###############################################################
#  Generated by:      Cadence Innovus 22.17-s086_1
#  OS:                Linux x86_64(Host ID vlsiktmt)
#  Generated on:      Sun Apr 12 21:09:17 2026
#  Design:            Adder32
#  Command:           write_lef_abstract -noCutObs ./outputs/innovus.lef
###############################################################

VERSION 5.8 ;

BUSBITCHARS "[]" ;
DIVIDERCHAR "/" ;

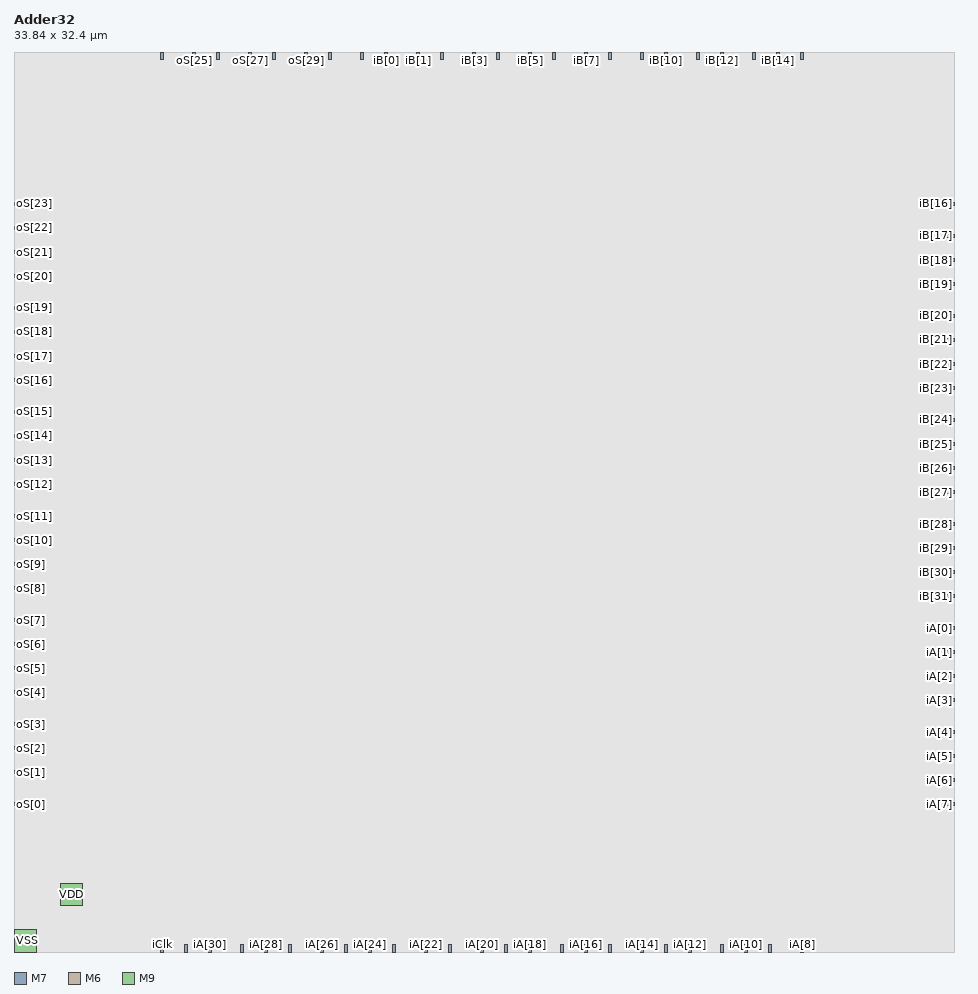
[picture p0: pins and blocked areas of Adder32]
MACRO Adder32
  CLASS BLOCK ;
  SIZE 33.840000 BY 32.400000 ;
  FOREIGN Adder32 0.000000 0.000000 ;
  ORIGIN 0 0 ;
  SYMMETRY X Y R90 ;
  PIN iClk
    DIRECTION INPUT ;
    USE SIGNAL ;
    PORT
      LAYER M7 ;
        RECT 5.264000 0.000000 5.392000 0.280000 ;
    END
  END iClk
  PIN iA[31]
    DIRECTION INPUT ;
    USE SIGNAL ;
    PORT
      LAYER M7 ;
        RECT 6.128000 0.000000 6.256000 0.280000 ;
    END
  END iA[31]
  PIN iA[30]
    DIRECTION INPUT ;
    USE SIGNAL ;
    PORT
      LAYER M7 ;
        RECT 6.992000 0.000000 7.120000 0.280000 ;
    END
  END iA[30]
  PIN iA[29]
    DIRECTION INPUT ;
    USE SIGNAL ;
    PORT
      LAYER M7 ;
        RECT 8.144000 0.000000 8.272000 0.280000 ;
    END
  END iA[29]
  PIN iA[28]
    DIRECTION INPUT ;
    USE SIGNAL ;
    PORT
      LAYER M7 ;
        RECT 9.008000 0.000000 9.136000 0.280000 ;
    END
  END iA[28]
  PIN iA[27]
    DIRECTION INPUT ;
    USE SIGNAL ;
    PORT
      LAYER M7 ;
        RECT 9.872000 0.000000 10.000000 0.280000 ;
    END
  END iA[27]
  PIN iA[26]
    DIRECTION INPUT ;
    USE SIGNAL ;
    PORT
      LAYER M7 ;
        RECT 11.024000 0.000000 11.152000 0.280000 ;
    END
  END iA[26]
  PIN iA[25]
    DIRECTION INPUT ;
    USE SIGNAL ;
    PORT
      LAYER M7 ;
        RECT 11.888000 0.000000 12.016000 0.280000 ;
    END
  END iA[25]
  PIN iA[24]
    DIRECTION INPUT ;
    USE SIGNAL ;
    PORT
      LAYER M7 ;
        RECT 12.752000 0.000000 12.880000 0.280000 ;
    END
  END iA[24]
  PIN iA[23]
    DIRECTION INPUT ;
    USE SIGNAL ;
    PORT
      LAYER M7 ;
        RECT 13.616000 0.000000 13.744000 0.280000 ;
    END
  END iA[23]
  PIN iA[22]
    DIRECTION INPUT ;
    USE SIGNAL ;
    PORT
      LAYER M7 ;
        RECT 14.768000 0.000000 14.896000 0.280000 ;
    END
  END iA[22]
  PIN iA[21]
    DIRECTION INPUT ;
    USE SIGNAL ;
    PORT
      LAYER M7 ;
        RECT 15.632000 0.000000 15.760000 0.280000 ;
    END
  END iA[21]
  PIN iA[20]
    DIRECTION INPUT ;
    USE SIGNAL ;
    PORT
      LAYER M7 ;
        RECT 16.784000 0.000000 16.912000 0.280000 ;
    END
  END iA[20]
  PIN iA[19]
    DIRECTION INPUT ;
    USE SIGNAL ;
    PORT
      LAYER M7 ;
        RECT 17.648000 0.000000 17.776000 0.280000 ;
    END
  END iA[19]
  PIN iA[18]
    DIRECTION INPUT ;
    USE SIGNAL ;
    PORT
      LAYER M7 ;
        RECT 18.512000 0.000000 18.640000 0.280000 ;
    END
  END iA[18]
  PIN iA[17]
    DIRECTION INPUT ;
    USE SIGNAL ;
    PORT
      LAYER M7 ;
        RECT 19.664000 0.000000 19.792000 0.280000 ;
    END
  END iA[17]
  PIN iA[16]
    DIRECTION INPUT ;
    USE SIGNAL ;
    PORT
      LAYER M7 ;
        RECT 20.528000 0.000000 20.656000 0.280000 ;
    END
  END iA[16]
  PIN iA[15]
    DIRECTION INPUT ;
    USE SIGNAL ;
    PORT
      LAYER M7 ;
        RECT 21.392000 0.000000 21.520000 0.280000 ;
    END
  END iA[15]
  PIN iA[14]
    DIRECTION INPUT ;
    USE SIGNAL ;
    PORT
      LAYER M7 ;
        RECT 22.544000 0.000000 22.672000 0.280000 ;
    END
  END iA[14]
  PIN iA[13]
    DIRECTION INPUT ;
    USE SIGNAL ;
    PORT
      LAYER M7 ;
        RECT 23.408000 0.000000 23.536000 0.280000 ;
    END
  END iA[13]
  PIN iA[12]
    DIRECTION INPUT ;
    USE SIGNAL ;
    PORT
      LAYER M7 ;
        RECT 24.272000 0.000000 24.400000 0.280000 ;
    END
  END iA[12]
  PIN iA[11]
    DIRECTION INPUT ;
    USE SIGNAL ;
    PORT
      LAYER M7 ;
        RECT 25.424000 0.000000 25.552000 0.280000 ;
    END
  END iA[11]
  PIN iA[10]
    DIRECTION INPUT ;
    USE SIGNAL ;
    PORT
      LAYER M7 ;
        RECT 26.288000 0.000000 26.416000 0.280000 ;
    END
  END iA[10]
  PIN iA[9]
    DIRECTION INPUT ;
    USE SIGNAL ;
    PORT
      LAYER M7 ;
        RECT 27.152000 0.000000 27.280000 0.280000 ;
    END
  END iA[9]
  PIN iA[8]
    DIRECTION INPUT ;
    USE SIGNAL ;
    PORT
      LAYER M7 ;
        RECT 28.304000 0.000000 28.432000 0.280000 ;
    END
  END iA[8]
  PIN iA[7]
    DIRECTION INPUT ;
    USE SIGNAL ;
    PORT
      LAYER M6 ;
        RECT 33.560000 5.264000 33.840000 5.392000 ;
    END
  END iA[7]
  PIN iA[6]
    DIRECTION INPUT ;
    USE SIGNAL ;
    PORT
      LAYER M6 ;
        RECT 33.560000 6.128000 33.840000 6.256000 ;
    END
  END iA[6]
  PIN iA[5]
    DIRECTION INPUT ;
    USE SIGNAL ;
    PORT
      LAYER M6 ;
        RECT 33.560000 6.992000 33.840000 7.120000 ;
    END
  END iA[5]
  PIN iA[4]
    DIRECTION INPUT ;
    USE SIGNAL ;
    PORT
      LAYER M6 ;
        RECT 33.560000 7.856000 33.840000 7.984000 ;
    END
  END iA[4]
  PIN iA[3]
    DIRECTION INPUT ;
    USE SIGNAL ;
    PORT
      LAYER M6 ;
        RECT 33.560000 9.008000 33.840000 9.136000 ;
    END
  END iA[3]
  PIN iA[2]
    DIRECTION INPUT ;
    USE SIGNAL ;
    PORT
      LAYER M6 ;
        RECT 33.560000 9.872000 33.840000 10.000000 ;
    END
  END iA[2]
  PIN iA[1]
    DIRECTION INPUT ;
    USE SIGNAL ;
    PORT
      LAYER M6 ;
        RECT 33.560000 10.736000 33.840000 10.864000 ;
    END
  END iA[1]
  PIN iA[0]
    DIRECTION INPUT ;
    USE SIGNAL ;
    PORT
      LAYER M6 ;
        RECT 33.560000 11.600000 33.840000 11.728000 ;
    END
  END iA[0]
  PIN iB[31]
    DIRECTION INPUT ;
    USE SIGNAL ;
    PORT
      LAYER M6 ;
        RECT 33.560000 12.752000 33.840000 12.880000 ;
    END
  END iB[31]
  PIN iB[30]
    DIRECTION INPUT ;
    USE SIGNAL ;
    PORT
      LAYER M6 ;
        RECT 33.560000 13.616000 33.840000 13.744000 ;
    END
  END iB[30]
  PIN iB[29]
    DIRECTION INPUT ;
    USE SIGNAL ;
    PORT
      LAYER M6 ;
        RECT 33.560000 14.480000 33.840000 14.608000 ;
    END
  END iB[29]
  PIN iB[28]
    DIRECTION INPUT ;
    USE SIGNAL ;
    PORT
      LAYER M6 ;
        RECT 33.560000 15.344000 33.840000 15.472000 ;
    END
  END iB[28]
  PIN iB[27]
    DIRECTION INPUT ;
    USE SIGNAL ;
    PORT
      LAYER M6 ;
        RECT 33.560000 16.496000 33.840000 16.624000 ;
    END
  END iB[27]
  PIN iB[26]
    DIRECTION INPUT ;
    USE SIGNAL ;
    PORT
      LAYER M6 ;
        RECT 33.560000 17.360000 33.840000 17.488000 ;
    END
  END iB[26]
  PIN iB[25]
    DIRECTION INPUT ;
    USE SIGNAL ;
    PORT
      LAYER M6 ;
        RECT 33.560000 18.224000 33.840000 18.352000 ;
    END
  END iB[25]
  PIN iB[24]
    DIRECTION INPUT ;
    USE SIGNAL ;
    PORT
      LAYER M6 ;
        RECT 33.560000 19.088000 33.840000 19.216000 ;
    END
  END iB[24]
  PIN iB[23]
    DIRECTION INPUT ;
    USE SIGNAL ;
    PORT
      LAYER M6 ;
        RECT 33.560000 20.240000 33.840000 20.368000 ;
    END
  END iB[23]
  PIN iB[22]
    DIRECTION INPUT ;
    USE SIGNAL ;
    PORT
      LAYER M6 ;
        RECT 33.560000 21.104000 33.840000 21.232000 ;
    END
  END iB[22]
  PIN iB[21]
    DIRECTION INPUT ;
    USE SIGNAL ;
    PORT
      LAYER M6 ;
        RECT 33.560000 21.968000 33.840000 22.096000 ;
    END
  END iB[21]
  PIN iB[20]
    DIRECTION INPUT ;
    USE SIGNAL ;
    PORT
      LAYER M6 ;
        RECT 33.560000 22.832000 33.840000 22.960000 ;
    END
  END iB[20]
  PIN iB[19]
    DIRECTION INPUT ;
    USE SIGNAL ;
    PORT
      LAYER M6 ;
        RECT 33.560000 23.984000 33.840000 24.112000 ;
    END
  END iB[19]
  PIN iB[18]
    DIRECTION INPUT ;
    USE SIGNAL ;
    PORT
      LAYER M6 ;
        RECT 33.560000 24.848000 33.840000 24.976000 ;
    END
  END iB[18]
  PIN iB[17]
    DIRECTION INPUT ;
    USE SIGNAL ;
    PORT
      LAYER M6 ;
        RECT 33.560000 25.712000 33.840000 25.840000 ;
    END
  END iB[17]
  PIN iB[16]
    DIRECTION INPUT ;
    USE SIGNAL ;
    PORT
      LAYER M6 ;
        RECT 33.560000 26.864000 33.840000 26.992000 ;
    END
  END iB[16]
  PIN iB[15]
    DIRECTION INPUT ;
    USE SIGNAL ;
    PORT
      LAYER M7 ;
        RECT 28.304000 32.120000 28.432000 32.400000 ;
    END
  END iB[15]
  PIN iB[14]
    DIRECTION INPUT ;
    USE SIGNAL ;
    PORT
      LAYER M7 ;
        RECT 27.440000 32.120000 27.568000 32.400000 ;
    END
  END iB[14]
  PIN iB[13]
    DIRECTION INPUT ;
    USE SIGNAL ;
    PORT
      LAYER M7 ;
        RECT 26.576000 32.120000 26.704000 32.400000 ;
    END
  END iB[13]
  PIN iB[12]
    DIRECTION INPUT ;
    USE SIGNAL ;
    PORT
      LAYER M7 ;
        RECT 25.424000 32.120000 25.552000 32.400000 ;
    END
  END iB[12]
  PIN iB[11]
    DIRECTION INPUT ;
    USE SIGNAL ;
    PORT
      LAYER M7 ;
        RECT 24.560000 32.120000 24.688000 32.400000 ;
    END
  END iB[11]
  PIN iB[10]
    DIRECTION INPUT ;
    USE SIGNAL ;
    PORT
      LAYER M7 ;
        RECT 23.408000 32.120000 23.536000 32.400000 ;
    END
  END iB[10]
  PIN iB[9]
    DIRECTION INPUT ;
    USE SIGNAL ;
    PORT
      LAYER M7 ;
        RECT 22.544000 32.120000 22.672000 32.400000 ;
    END
  END iB[9]
  PIN iB[8]
    DIRECTION INPUT ;
    USE SIGNAL ;
    PORT
      LAYER M7 ;
        RECT 21.392000 32.120000 21.520000 32.400000 ;
    END
  END iB[8]
  PIN iB[7]
    DIRECTION INPUT ;
    USE SIGNAL ;
    PORT
      LAYER M7 ;
        RECT 20.528000 32.120000 20.656000 32.400000 ;
    END
  END iB[7]
  PIN iB[6]
    DIRECTION INPUT ;
    USE SIGNAL ;
    PORT
      LAYER M7 ;
        RECT 19.376000 32.120000 19.504000 32.400000 ;
    END
  END iB[6]
  PIN iB[5]
    DIRECTION INPUT ;
    USE SIGNAL ;
    PORT
      LAYER M7 ;
        RECT 18.512000 32.120000 18.640000 32.400000 ;
    END
  END iB[5]
  PIN iB[4]
    DIRECTION INPUT ;
    USE SIGNAL ;
    PORT
      LAYER M7 ;
        RECT 17.360000 32.120000 17.488000 32.400000 ;
    END
  END iB[4]
  PIN iB[3]
    DIRECTION INPUT ;
    USE SIGNAL ;
    PORT
      LAYER M7 ;
        RECT 16.496000 32.120000 16.624000 32.400000 ;
    END
  END iB[3]
  PIN iB[2]
    DIRECTION INPUT ;
    USE SIGNAL ;
    PORT
      LAYER M7 ;
        RECT 15.344000 32.120000 15.472000 32.400000 ;
    END
  END iB[2]
  PIN iB[1]
    DIRECTION INPUT ;
    USE SIGNAL ;
    PORT
      LAYER M7 ;
        RECT 14.480000 32.120000 14.608000 32.400000 ;
    END
  END iB[1]
  PIN iB[0]
    DIRECTION INPUT ;
    USE SIGNAL ;
    PORT
      LAYER M7 ;
        RECT 13.328000 32.120000 13.456000 32.400000 ;
    END
  END iB[0]
  PIN oS[31]
    DIRECTION OUTPUT ;
    USE SIGNAL ;
    PORT
      LAYER M7 ;
        RECT 12.464000 32.120000 12.592000 32.400000 ;
    END
  END oS[31]
  PIN oS[30]
    DIRECTION OUTPUT ;
    USE SIGNAL ;
    PORT
      LAYER M7 ;
        RECT 11.312000 32.120000 11.440000 32.400000 ;
    END
  END oS[30]
  PIN oS[29]
    DIRECTION OUTPUT ;
    USE SIGNAL ;
    PORT
      LAYER M7 ;
        RECT 10.448000 32.120000 10.576000 32.400000 ;
    END
  END oS[29]
  PIN oS[28]
    DIRECTION OUTPUT ;
    USE SIGNAL ;
    PORT
      LAYER M7 ;
        RECT 9.296000 32.120000 9.424000 32.400000 ;
    END
  END oS[28]
  PIN oS[27]
    DIRECTION OUTPUT ;
    USE SIGNAL ;
    PORT
      LAYER M7 ;
        RECT 8.432000 32.120000 8.560000 32.400000 ;
    END
  END oS[27]
  PIN oS[26]
    DIRECTION OUTPUT ;
    USE SIGNAL ;
    PORT
      LAYER M7 ;
        RECT 7.280000 32.120000 7.408000 32.400000 ;
    END
  END oS[26]
  PIN oS[25]
    DIRECTION OUTPUT ;
    USE SIGNAL ;
    PORT
      LAYER M7 ;
        RECT 6.416000 32.120000 6.544000 32.400000 ;
    END
  END oS[25]
  PIN oS[24]
    DIRECTION OUTPUT ;
    USE SIGNAL ;
    PORT
      LAYER M7 ;
        RECT 5.264000 32.120000 5.392000 32.400000 ;
    END
  END oS[24]
  PIN oS[23]
    DIRECTION OUTPUT ;
    USE SIGNAL ;
    PORT
      LAYER M6 ;
        RECT 0.000000 26.864000 0.280000 26.992000 ;
    END
  END oS[23]
  PIN oS[22]
    DIRECTION OUTPUT ;
    USE SIGNAL ;
    PORT
      LAYER M6 ;
        RECT 0.000000 26.000000 0.280000 26.128000 ;
    END
  END oS[22]
  PIN oS[21]
    DIRECTION OUTPUT ;
    USE SIGNAL ;
    PORT
      LAYER M6 ;
        RECT 0.000000 25.136000 0.280000 25.264000 ;
    END
  END oS[21]
  PIN oS[20]
    DIRECTION OUTPUT ;
    USE SIGNAL ;
    PORT
      LAYER M6 ;
        RECT 0.000000 24.272000 0.280000 24.400000 ;
    END
  END oS[20]
  PIN oS[19]
    DIRECTION OUTPUT ;
    USE SIGNAL ;
    PORT
      LAYER M6 ;
        RECT 0.000000 23.120000 0.280000 23.248000 ;
    END
  END oS[19]
  PIN oS[18]
    DIRECTION OUTPUT ;
    USE SIGNAL ;
    PORT
      LAYER M6 ;
        RECT 0.000000 22.256000 0.280000 22.384000 ;
    END
  END oS[18]
  PIN oS[17]
    DIRECTION OUTPUT ;
    USE SIGNAL ;
    PORT
      LAYER M6 ;
        RECT 0.000000 21.392000 0.280000 21.520000 ;
    END
  END oS[17]
  PIN oS[16]
    DIRECTION OUTPUT ;
    USE SIGNAL ;
    PORT
      LAYER M6 ;
        RECT 0.000000 20.528000 0.280000 20.656000 ;
    END
  END oS[16]
  PIN oS[15]
    DIRECTION OUTPUT ;
    USE SIGNAL ;
    PORT
      LAYER M6 ;
        RECT 0.000000 19.376000 0.280000 19.504000 ;
    END
  END oS[15]
  PIN oS[14]
    DIRECTION OUTPUT ;
    USE SIGNAL ;
    PORT
      LAYER M6 ;
        RECT 0.000000 18.512000 0.280000 18.640000 ;
    END
  END oS[14]
  PIN oS[13]
    DIRECTION OUTPUT ;
    USE SIGNAL ;
    PORT
      LAYER M6 ;
        RECT 0.000000 17.648000 0.280000 17.776000 ;
    END
  END oS[13]
  PIN oS[12]
    DIRECTION OUTPUT ;
    USE SIGNAL ;
    PORT
      LAYER M6 ;
        RECT 0.000000 16.784000 0.280000 16.912000 ;
    END
  END oS[12]
  PIN oS[11]
    DIRECTION OUTPUT ;
    USE SIGNAL ;
    PORT
      LAYER M6 ;
        RECT 0.000000 15.632000 0.280000 15.760000 ;
    END
  END oS[11]
  PIN oS[10]
    DIRECTION OUTPUT ;
    USE SIGNAL ;
    PORT
      LAYER M6 ;
        RECT 0.000000 14.768000 0.280000 14.896000 ;
    END
  END oS[10]
  PIN oS[9]
    DIRECTION OUTPUT ;
    USE SIGNAL ;
    PORT
      LAYER M6 ;
        RECT 0.000000 13.904000 0.280000 14.032000 ;
    END
  END oS[9]
  PIN oS[8]
    DIRECTION OUTPUT ;
    USE SIGNAL ;
    PORT
      LAYER M6 ;
        RECT 0.000000 13.040000 0.280000 13.168000 ;
    END
  END oS[8]
  PIN oS[7]
    DIRECTION OUTPUT ;
    USE SIGNAL ;
    PORT
      LAYER M6 ;
        RECT 0.000000 11.888000 0.280000 12.016000 ;
    END
  END oS[7]
  PIN oS[6]
    DIRECTION OUTPUT ;
    USE SIGNAL ;
    PORT
      LAYER M6 ;
        RECT 0.000000 11.024000 0.280000 11.152000 ;
    END
  END oS[6]
  PIN oS[5]
    DIRECTION OUTPUT ;
    USE SIGNAL ;
    PORT
      LAYER M6 ;
        RECT 0.000000 10.160000 0.280000 10.288000 ;
    END
  END oS[5]
  PIN oS[4]
    DIRECTION OUTPUT ;
    USE SIGNAL ;
    PORT
      LAYER M6 ;
        RECT 0.000000 9.296000 0.280000 9.424000 ;
    END
  END oS[4]
  PIN oS[3]
    DIRECTION OUTPUT ;
    USE SIGNAL ;
    PORT
      LAYER M6 ;
        RECT 0.000000 8.144000 0.280000 8.272000 ;
    END
  END oS[3]
  PIN oS[2]
    DIRECTION OUTPUT ;
    USE SIGNAL ;
    PORT
      LAYER M6 ;
        RECT 0.000000 7.280000 0.280000 7.408000 ;
    END
  END oS[2]
  PIN oS[1]
    DIRECTION OUTPUT ;
    USE SIGNAL ;
    PORT
      LAYER M6 ;
        RECT 0.000000 6.416000 0.280000 6.544000 ;
    END
  END oS[1]
  PIN oS[0]
    DIRECTION OUTPUT ;
    USE SIGNAL ;
    PORT
      LAYER M6 ;
        RECT 0.000000 5.264000 0.280000 5.392000 ;
    END
  END oS[0]
  PIN VSS
    DIRECTION INOUT ;
    USE GROUND ;
    PORT
      LAYER M9 ;
        RECT 0.000000 0.000000 0.800000 0.800000 ;
    END
  END VSS
  PIN VDD
    DIRECTION INOUT ;
    USE POWER ;
    PORT
      LAYER M9 ;
        RECT 1.680000 1.680000 2.480000 2.480000 ;
    END
  END VDD
  OBS
    LAYER M1 ;
      RECT 0.000000 0.000000 33.840000 32.400000 ;
    LAYER M2 ;
      RECT 0.000000 0.000000 33.840000 32.400000 ;
    LAYER M3 ;
      RECT 0.000000 0.000000 33.840000 32.400000 ;
    LAYER M4 ;
      RECT 0.000000 0.000000 33.840000 32.400000 ;
    LAYER M5 ;
      RECT 0.000000 0.000000 33.840000 32.400000 ;
    LAYER M6 ;
      RECT 0.000000 0.000000 33.840000 32.400000 ;
    LAYER M7 ;
      RECT 0.000000 0.000000 33.840000 32.400000 ;
    LAYER M8 ;
      RECT 0.000000 0.000000 33.840000 32.400000 ;
    LAYER M9 ;
      RECT 0.000000 0.000000 33.840000 32.400000 ;
    LAYER Pad ;
      RECT 0.000000 0.000000 33.840000 32.400000 ;
  END
END Adder32

END LIBRARY
